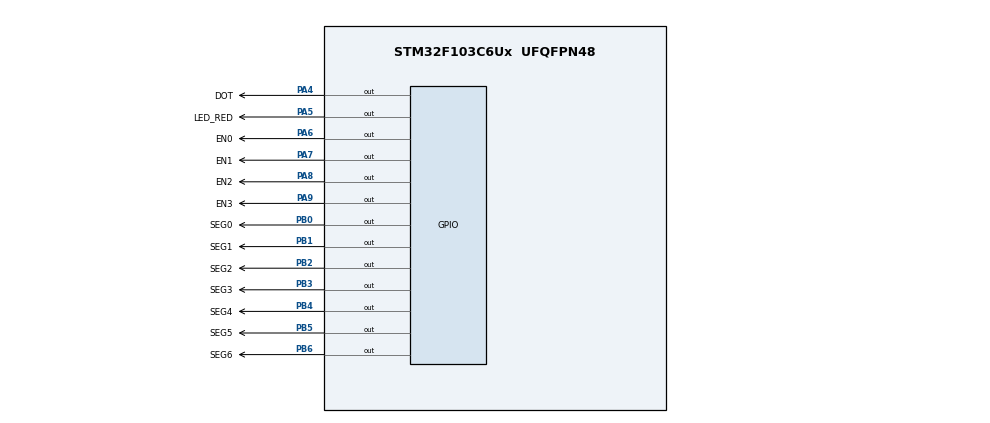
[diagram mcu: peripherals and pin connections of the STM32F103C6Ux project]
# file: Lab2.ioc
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Mcu.Family=STM32F1
Mcu.Name=STM32F103C6Ux
Mcu.Package=UFQFPN48
NVIC.PriorityGroup=NVIC_PRIORITYGROUP_4
NVIC.TIM2_IRQn=true\:0\:0\:false\:false\:true\:true\:true
PA4.GPIO_Label=DOT
PA4.Signal=GPIO_Output
PA5.GPIO_Label=LED_RED
PA5.Signal=GPIO_Output
PA6.GPIO_Label=EN0
PA6.Signal=GPIO_Output
PA7.GPIO_Label=EN1
PA7.Signal=GPIO_Output
PA8.GPIO_Label=EN2
PA8.Signal=GPIO_Output
PA9.GPIO_Label=EN3
PA9.Signal=GPIO_Output
PB0.GPIO_Label=SEG0
PB0.Signal=GPIO_Output
PB1.GPIO_Label=SEG1
PB1.Signal=GPIO_Output
PB2.GPIO_Label=SEG2
PB2.Signal=GPIO_Output
PB3.GPIO_Label=SEG3
PB3.Signal=GPIO_Output
PB4.GPIO_Label=SEG4
PB4.Signal=GPIO_Output
PB5.GPIO_Label=SEG5
PB5.Signal=GPIO_Output
PB6.GPIO_Label=SEG6
PB6.Signal=GPIO_Output
ProjectManager.HeapSize=0x200
ProjectManager.StackSize=0x400
ProjectManager.TargetToolchain=STM32CubeIDE
RCC.APB1Freq_Value=8000000
RCC.APB2Freq_Value=8000000
TIM2.Period=9
TIM2.Prescaler=7999
VP_SYS_VS_ND.Mode=No_Debug
VP_TIM2_VS_ClockSourceINT.Mode=Internal
board=custom

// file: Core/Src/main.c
/* USER CODE BEGIN Header */
/**
  ******************************************************************************
  * @file           : main.c
  * @brief          : Main program body
  ******************************************************************************
  * @attention
  *
  * <h2><center>&copy; Copyright (c) 2023 STMicroelectronics.
  * All rights reserved.</center></h2>
  *
  * This software component is licensed by ST under BSD 3-Clause license,
  * the "License"; You may not use this file except in compliance with the
  * License. You may obtain a copy of the License at:
  *                        opensource.org/licenses/BSD-3-Clause
  *
  ******************************************************************************
  */
/* USER CODE END Header */
#include "main.h"
#include "software_timer.h"

/* USER CODE BEGIN PM */
#define setLed 50 //led red 500ms
#define setDot 100 //1s
#define setSegment 50 //500ms
int status =1;
int counterLed = setLed;
int counterDot = setDot;
int counterSeg = setSegment;
const int MAX_LED = 4;
int index_led = 0;
int led_buffer[4] = {1,3,0,4};
int hour = 23, minute = 59, second = 55;
/* USER CODE END PM */

TIM_HandleTypeDef htim2;

void SystemClock_Config(void);
static void MX_GPIO_Init(void);
static void MX_TIM2_Init(void);

/* USER CODE BEGIN 0 */
void display7SEG (int counter){
	if(counter==0){
		HAL_GPIO_WritePin(SEG0_GPIO_Port, SEG0_Pin, RESET);
		HAL_GPIO_WritePin(SEG1_GPIO_Port, SEG1_Pin, RESET);
		HAL_GPIO_WritePin(SEG2_GPIO_Port, SEG2_Pin, RESET);
		HAL_GPIO_WritePin(SEG3_GPIO_Port, SEG3_Pin, RESET);
		HAL_GPIO_WritePin(SEG4_GPIO_Port, SEG4_Pin, RESET);
		HAL_GPIO_WritePin(SEG5_GPIO_Port, SEG5_Pin, RESET);
		HAL_GPIO_WritePin(SEG6_GPIO_Port, SEG6_Pin, SET);
	}
	if(counter==1){
		HAL_GPIO_WritePin(SEG0_GPIO_Port, SEG0_Pin, SET);
		HAL_GPIO_WritePin(SEG1_GPIO_Port, SEG1_Pin, RESET);
		HAL_GPIO_WritePin(SEG2_GPIO_Port, SEG2_Pin, RESET);
		HAL_GPIO_WritePin(SEG3_GPIO_Port, SEG3_Pin, SET);
		HAL_GPIO_WritePin(SEG4_GPIO_Port, SEG4_Pin, SET);
		HAL_GPIO_WritePin(SEG5_GPIO_Port, SEG5_Pin, SET);
		HAL_GPIO_WritePin(SEG6_GPIO_Port, SEG6_Pin, SET);
	}
	if(counter==2){
		HAL_GPIO_WritePin(SEG0_GPIO_Port, SEG0_Pin, RESET);
		HAL_GPIO_WritePin(SEG1_GPIO_Port, SEG1_Pin, RESET);
		HAL_GPIO_WritePin(SEG2_GPIO_Port, SEG2_Pin, SET);
		HAL_GPIO_WritePin(SEG3_GPIO_Port, SEG3_Pin, RESET);
		HAL_GPIO_WritePin(SEG4_GPIO_Port, SEG4_Pin, RESET);
		HAL_GPIO_WritePin(SEG5_GPIO_Port, SEG5_Pin, SET);
		HAL_GPIO_WritePin(SEG6_GPIO_Port, SEG6_Pin, RESET);
	}
	if(counter==3){
		HAL_GPIO_WritePin(SEG0_GPIO_Port, SEG0_Pin, RESET);
		HAL_GPIO_WritePin(SEG1_GPIO_Port, SEG1_Pin, RESET);
		HAL_GPIO_WritePin(SEG2_GPIO_Port, SEG2_Pin, RESET);
		HAL_GPIO_WritePin(SEG3_GPIO_Port, SEG3_Pin, RESET);
		HAL_GPIO_WritePin(SEG4_GPIO_Port, SEG4_Pin, SET);
		HAL_GPIO_WritePin(SEG5_GPIO_Port, SEG5_Pin, SET);
		HAL_GPIO_WritePin(SEG6_GPIO_Port, SEG6_Pin, RESET);
	}
	if(counter==4){
		HAL_GPIO_WritePin(SEG0_GPIO_Port, SEG0_Pin, SET);
		HAL_GPIO_WritePin(SEG1_GPIO_Port, SEG1_Pin, RESET);
		HAL_GPIO_WritePin(SEG2_GPIO_Port, SEG2_Pin, RESET);
		HAL_GPIO_WritePin(SEG3_GPIO_Port, SEG3_Pin, SET);
		HAL_GPIO_WritePin(SEG4_GPIO_Port, SEG4_Pin, SET);
		HAL_GPIO_WritePin(SEG5_GPIO_Port, SEG5_Pin, RESET);
		HAL_GPIO_WritePin(SEG6_GPIO_Port, SEG6_Pin, RESET);
	}
	if(counter==5){
		HAL_GPIO_WritePin(SEG0_GPIO_Port, SEG0_Pin, RESET);
		HAL_GPIO_WritePin(SEG1_GPIO_Port, SEG1_Pin, SET);
		HAL_GPIO_WritePin(SEG2_GPIO_Port, SEG2_Pin, RESET);
		HAL_GPIO_WritePin(SEG3_GPIO_Port, SEG3_Pin, RESET);
		HAL_GPIO_WritePin(SEG4_GPIO_Port, SEG4_Pin, SET);
		HAL_GPIO_WritePin(SEG5_GPIO_Port, SEG5_Pin, RESET);
		HAL_GPIO_WritePin(SEG6_GPIO_Port, SEG6_Pin, RESET);
	}
	if(counter==6){
		HAL_GPIO_WritePin(SEG0_GPIO_Port, SEG0_Pin, RESET);
		HAL_GPIO_WritePin(SEG1_GPIO_Port, SEG1_Pin, SET);
		HAL_GPIO_WritePin(SEG2_GPIO_Port, SEG2_Pin, RESET);
		HAL_GPIO_WritePin(SEG3_GPIO_Port, SEG3_Pin, RESET);
		HAL_GPIO_WritePin(SEG4_GPIO_Port, SEG4_Pin, RESET);
		HAL_GPIO_WritePin(SEG5_GPIO_Port, SEG5_Pin, RESET);
		HAL_GPIO_WritePin(SEG6_GPIO_Port, SEG6_Pin, RESET);
	}
	if(counter==7){
		HAL_GPIO_WritePin(SEG0_GPIO_Port, SEG0_Pin, RESET);
		HAL_GPIO_WritePin(SEG1_GPIO_Port, SEG1_Pin, RESET);
		HAL_GPIO_WritePin(SEG2_GPIO_Port, SEG2_Pin, RESET);
		HAL_GPIO_WritePin(SEG3_GPIO_Port, SEG3_Pin, SET);
		HAL_GPIO_WritePin(SEG4_GPIO_Port, SEG4_Pin, SET);
		HAL_GPIO_WritePin(SEG5_GPIO_Port, SEG5_Pin, SET);
		HAL_GPIO_WritePin(SEG6_GPIO_Port, SEG6_Pin, SET);
	}
	if(counter==8){
		HAL_GPIO_WritePin(SEG0_GPIO_Port, SEG0_Pin, RESET);
		HAL_GPIO_WritePin(SEG1_GPIO_Port, SEG1_Pin, RESET);
		HAL_GPIO_WritePin(SEG2_GPIO_Port, SEG2_Pin, RESET);
		HAL_GPIO_WritePin(SEG3_GPIO_Port, SEG3_Pin, RESET);
		HAL_GPIO_WritePin(SEG4_GPIO_Port, SEG4_Pin, RESET);
		HAL_GPIO_WritePin(SEG5_GPIO_Port, SEG5_Pin, RESET);
		HAL_GPIO_WritePin(SEG6_GPIO_Port, SEG6_Pin, RESET);
	}
	if(counter==9){
		HAL_GPIO_WritePin(SEG0_GPIO_Port, SEG0_Pin, RESET);
		HAL_GPIO_WritePin(SEG1_GPIO_Port, SEG1_Pin, RESET);
		HAL_GPIO_WritePin(SEG2_GPIO_Port, SEG2_Pin, RESET);
		HAL_GPIO_WritePin(SEG3_GPIO_Port, SEG3_Pin, RESET);
		HAL_GPIO_WritePin(SEG4_GPIO_Port, SEG4_Pin, SET);
		HAL_GPIO_WritePin(SEG5_GPIO_Port, SEG5_Pin, RESET);
		HAL_GPIO_WritePin(SEG6_GPIO_Port, SEG6_Pin, RESET);
	}
}
void updateClockBuffer(){
	led_buffer[0] = hour/10;
	led_buffer[1] = hour%10;
	led_buffer[2] = minute/10;
	led_buffer[3] = minute%10;
}

void update7SEG(int index){
	display7SEG(led_buffer[index]);
    switch (index){
	case 0:
		// Display the first 7 SEG with led_buffer [0]
		HAL_GPIO_WritePin(EN0_GPIO_Port, EN0_Pin, RESET);
		HAL_GPIO_WritePin(EN1_GPIO_Port, EN1_Pin, SET);
		HAL_GPIO_WritePin(EN2_GPIO_Port, EN2_Pin, SET);
		HAL_GPIO_WritePin(EN3_GPIO_Port, EN3_Pin, SET);
		break ;
	case 1:
		// Display the second 7 SEG with led_buffer [1]
		HAL_GPIO_WritePin(EN0_GPIO_Port, EN0_Pin, SET);
		HAL_GPIO_WritePin(EN1_GPIO_Port, EN1_Pin, RESET);
		HAL_GPIO_WritePin(EN2_GPIO_Port, EN2_Pin, SET);
		HAL_GPIO_WritePin(EN3_GPIO_Port, EN3_Pin, SET);
		break ;
	case 2:
		// Display the third 7 SEG with led_buffer [2]
		HAL_GPIO_WritePin(EN0_GPIO_Port, EN0_Pin, SET);
		HAL_GPIO_WritePin(EN1_GPIO_Port, EN1_Pin, SET);
		HAL_GPIO_WritePin(EN2_GPIO_Port, EN2_Pin, RESET);
		HAL_GPIO_WritePin(EN3_GPIO_Port, EN3_Pin, SET);
		break ;
	case 3:
		// Display the forth 7 SEG with led_buffer [3]
		HAL_GPIO_WritePin(EN0_GPIO_Port, EN0_Pin, SET);
		HAL_GPIO_WritePin(EN1_GPIO_Port, EN1_Pin, SET);
		HAL_GPIO_WritePin(EN2_GPIO_Port, EN2_Pin, SET);
		HAL_GPIO_WritePin(EN3_GPIO_Port, EN3_Pin, RESET);
		break ;
	default :
		break ;
	}
}
const int MAX_LED_MATRIX = 8;
int index_led_matrix = 0;
uint8_t matrix_buffer[8] = {0x01, 0x02, 0x03, 0x04, 0x05, 0x06, 0x07, 0x08};
void updateLEDMatrix(int index){
    switch (index){
        case 0:
        	//ENMx
        	HAL_GPIO_WritePin(ENM0_GPIO_Port, ENM0_Pin, RESET);
        	HAL_GPIO_WritePin(ENM1_GPIO_Port, ENM1_Pin, SET);
        	HAL_GPIO_WritePin(ENM2_GPIO_Port, ENM2_Pin, SET);
        	HAL_GPIO_WritePin(ENM3_GPIO_Port, ENM3_Pin, SET);
        	HAL_GPIO_WritePin(ENM4_GPIO_Port, ENM4_Pin, SET);
        	HAL_GPIO_WritePin(ENM5_GPIO_Port, ENM5_Pin, SET);
        	HAL_GPIO_WritePin(ENM6_GPIO_Port, ENM6_Pin, SET);
        	HAL_GPIO_WritePin(ENM7_GPIO_Port, ENM7_Pin, SET);
        	//ROWx
        	HAL_GPIO_WritePin(ROW0_GPIO_Port, ROW0_Pin, SET);
        	HAL_GPIO_WritePin(ROW1_GPIO_Port, ROW1_Pin, SET);
        	HAL_GPIO_WritePin(ROW2_GPIO_Port, ROW2_Pin, SET);
        	HAL_GPIO_WritePin(ROW3_GPIO_Port, ROW3_Pin, SET);
        	HAL_GPIO_WritePin(ROW4_GPIO_Port, ROW4_Pin, SET);
        	HAL_GPIO_WritePin(ROW5_GPIO_Port, ROW5_Pin, SET);
        	HAL_GPIO_WritePin(ROW6_GPIO_Port, ROW6_Pin, SET);
        	HAL_GPIO_WritePin(ROW7_GPIO_Port, ROW7_Pin, SET);
            break;
        case 1:
        	//ENMx
        	HAL_GPIO_WritePin(ENM0_GPIO_Port, ENM0_Pin, SET);
        	HAL_GPIO_WritePin(ENM1_GPIO_Port, ENM1_Pin, RESET);
        	HAL_GPIO_WritePin(ENM2_GPIO_Port, ENM2_Pin, SET);
        	HAL_GPIO_WritePin(ENM3_GPIO_Port, ENM3_Pin, SET);
        	HAL_GPIO_WritePin(ENM4_GPIO_Port, ENM4_Pin, SET);
        	HAL_GPIO_WritePin(ENM5_GPIO_Port, ENM5_Pin, SET);
        	HAL_GPIO_WritePin(ENM6_GPIO_Port, ENM6_Pin, SET);
        	HAL_GPIO_WritePin(ENM7_GPIO_Port, ENM7_Pin, SET);
        	//ROWx
        	HAL_GPIO_WritePin(ROW0_GPIO_Port, ROW0_Pin, SET);
        	HAL_GPIO_WritePin(ROW1_GPIO_Port, ROW1_Pin, RESET);
        	HAL_GPIO_WritePin(ROW2_GPIO_Port, ROW2_Pin, RESET);
        	HAL_GPIO_WritePin(ROW3_GPIO_Port, ROW3_Pin, RESET);
        	HAL_GPIO_WritePin(ROW4_GPIO_Port, ROW4_Pin, RESET);
        	HAL_GPIO_WritePin(ROW5_GPIO_Port, ROW5_Pin, RESET);
        	HAL_GPIO_WritePin(ROW6_GPIO_Port, ROW6_Pin, RESET);
        	HAL_GPIO_WritePin(ROW7_GPIO_Port, ROW7_Pin, RESET);
            break;
        case 2:
        	//ENMx
        	HAL_GPIO_WritePin(ENM0_GPIO_Port, ENM0_Pin, SET);
        	HAL_GPIO_WritePin(ENM1_GPIO_Port, ENM1_Pin, SET);
        	HAL_GPIO_WritePin(ENM2_GPIO_Port, ENM2_Pin, RESET);
        	HAL_GPIO_WritePin(ENM3_GPIO_Port, ENM3_Pin, SET);
        	HAL_GPIO_WritePin(ENM4_GPIO_Port, ENM4_Pin, SET);
        	HAL_GPIO_WritePin(ENM5_GPIO_Port, ENM5_Pin, SET);
        	HAL_GPIO_WritePin(ENM6_GPIO_Port, ENM6_Pin, SET);
        	HAL_GPIO_WritePin(ENM7_GPIO_Port, ENM7_Pin, SET);
        	//ROWx
        	HAL_GPIO_WritePin(ROW0_GPIO_Port, ROW0_Pin, RESET);
        	HAL_GPIO_WritePin(ROW1_GPIO_Port, ROW1_Pin, SET);
        	HAL_GPIO_WritePin(ROW2_GPIO_Port, ROW2_Pin, SET);
        	HAL_GPIO_WritePin(ROW3_GPIO_Port, ROW3_Pin, SET);
        	HAL_GPIO_WritePin(ROW4_GPIO_Port, ROW4_Pin, RESET);
        	HAL_GPIO_WritePin(ROW5_GPIO_Port, ROW5_Pin, SET);
        	HAL_GPIO_WritePin(ROW6_GPIO_Port, ROW6_Pin, SET);
        	HAL_GPIO_WritePin(ROW7_GPIO_Port, ROW7_Pin, SET);
            break;
        case 3:
        	//ENMx
        	HAL_GPIO_WritePin(ENM0_GPIO_Port, ENM0_Pin, SET);
        	HAL_GPIO_WritePin(ENM1_GPIO_Port, ENM1_Pin, SET);
        	HAL_GPIO_WritePin(ENM2_GPIO_Port, ENM2_Pin, SET);
        	HAL_GPIO_WritePin(ENM3_GPIO_Port, ENM3_Pin, RESET);
        	HAL_GPIO_WritePin(ENM4_GPIO_Port, ENM4_Pin, SET);
        	HAL_GPIO_WritePin(ENM5_GPIO_Port, ENM5_Pin, SET);
        	HAL_GPIO_WritePin(ENM6_GPIO_Port, ENM6_Pin, SET);
        	HAL_GPIO_WritePin(ENM7_GPIO_Port, ENM7_Pin, SET);
        	//ROWx
        	HAL_GPIO_WritePin(ROW0_GPIO_Port, ROW0_Pin, RESET);
        	HAL_GPIO_WritePin(ROW1_GPIO_Port, ROW1_Pin, SET);
        	HAL_GPIO_WritePin(ROW2_GPIO_Port, ROW2_Pin, SET);
        	HAL_GPIO_WritePin(ROW3_GPIO_Port, ROW3_Pin, SET);
        	HAL_GPIO_WritePin(ROW4_GPIO_Port, ROW4_Pin, RESET);
        	HAL_GPIO_WritePin(ROW5_GPIO_Port, ROW5_Pin, SET);
        	HAL_GPIO_WritePin(ROW6_GPIO_Port, ROW6_Pin, SET);
        	HAL_GPIO_WritePin(ROW7_GPIO_Port, ROW7_Pin, SET);
            break;
        case 4:
        	//ENMx
        	HAL_GPIO_WritePin(ENM0_GPIO_Port, ENM0_Pin, SET);
        	HAL_GPIO_WritePin(ENM1_GPIO_Port, ENM1_Pin, SET);
        	HAL_GPIO_WritePin(ENM2_GPIO_Port, ENM2_Pin, SET);
        	HAL_GPIO_WritePin(ENM3_GPIO_Port, ENM3_Pin, SET);
        	HAL_GPIO_WritePin(ENM4_GPIO_Port, ENM4_Pin, RESET);
        	HAL_GPIO_WritePin(ENM5_GPIO_Port, ENM5_Pin, SET);
        	HAL_GPIO_WritePin(ENM6_GPIO_Port, ENM6_Pin, SET);
        	HAL_GPIO_WritePin(ENM7_GPIO_Port, ENM7_Pin, SET);
        	//ROWx
        	HAL_GPIO_WritePin(ROW0_GPIO_Port, ROW0_Pin, RESET);
        	HAL_GPIO_WritePin(ROW1_GPIO_Port, ROW1_Pin, SET);
        	HAL_GPIO_WritePin(ROW2_GPIO_Port, ROW2_Pin, SET);
        	HAL_GPIO_WritePin(ROW3_GPIO_Port, ROW3_Pin, SET);
        	HAL_GPIO_WritePin(ROW4_GPIO_Port, ROW4_Pin, RESET);
        	HAL_GPIO_WritePin(ROW5_GPIO_Port, ROW5_Pin, SET);
        	HAL_GPIO_WritePin(ROW6_GPIO_Port, ROW6_Pin, SET);
        	HAL_GPIO_WritePin(ROW7_GPIO_Port, ROW7_Pin, SET);
            break;
        case 5:
        	//ENMx
        	HAL_GPIO_WritePin(ENM0_GPIO_Port, ENM0_Pin, SET);
        	HAL_GPIO_WritePin(ENM1_GPIO_Port, ENM1_Pin, SET);
        	HAL_GPIO_WritePin(ENM2_GPIO_Port, ENM2_Pin, SET);
        	HAL_GPIO_WritePin(ENM3_GPIO_Port, ENM3_Pin, SET);
        	HAL_GPIO_WritePin(ENM4_GPIO_Port, ENM4_Pin, SET);
        	HAL_GPIO_WritePin(ENM5_GPIO_Port, ENM5_Pin, RESET);
        	HAL_GPIO_WritePin(ENM6_GPIO_Port, ENM6_Pin, SET);
        	HAL_GPIO_WritePin(ENM7_GPIO_Port, ENM7_Pin, SET);
        	//ROWx
        	HAL_GPIO_WritePin(ROW0_GPIO_Port, ROW0_Pin, RESET);
        	HAL_GPIO_WritePin(ROW1_GPIO_Port, ROW1_Pin, SET);
        	HAL_GPIO_WritePin(ROW2_GPIO_Port, ROW2_Pin, SET);
        	HAL_GPIO_WritePin(ROW3_GPIO_Port, ROW3_Pin, SET);
        	HAL_GPIO_WritePin(ROW4_GPIO_Port, ROW4_Pin, RESET);
        	HAL_GPIO_WritePin(ROW5_GPIO_Port, ROW5_Pin, SET);
        	HAL_GPIO_WritePin(ROW6_GPIO_Port, ROW6_Pin, SET);
        	HAL_GPIO_WritePin(ROW7_GPIO_Port, ROW7_Pin, SET);
            break;
        case 6:
        	//ENMx
        	HAL_GPIO_WritePin(ENM0_GPIO_Port, ENM0_Pin, SET);
        	HAL_GPIO_WritePin(ENM1_GPIO_Port, ENM1_Pin, SET);
        	HAL_GPIO_WritePin(ENM2_GPIO_Port, ENM2_Pin, SET);
        	HAL_GPIO_WritePin(ENM3_GPIO_Port, ENM3_Pin, SET);
        	HAL_GPIO_WritePin(ENM4_GPIO_Port, ENM4_Pin, SET);
        	HAL_GPIO_WritePin(ENM5_GPIO_Port, ENM5_Pin, SET);
        	HAL_GPIO_WritePin(ENM6_GPIO_Port, ENM6_Pin, RESET);
        	HAL_GPIO_WritePin(ENM7_GPIO_Port, ENM7_Pin, SET);
        	//ROWx
        	HAL_GPIO_WritePin(ROW0_GPIO_Port, ROW0_Pin, SET);
        	HAL_GPIO_WritePin(ROW1_GPIO_Port, ROW1_Pin, RESET);
        	HAL_GPIO_WritePin(ROW2_GPIO_Port, ROW2_Pin, RESET);
        	HAL_GPIO_WritePin(ROW3_GPIO_Port, ROW3_Pin, RESET);
        	HAL_GPIO_WritePin(ROW4_GPIO_Port, ROW4_Pin, RESET);
        	HAL_GPIO_WritePin(ROW5_GPIO_Port, ROW5_Pin, RESET);
        	HAL_GPIO_WritePin(ROW6_GPIO_Port, ROW6_Pin, RESET);
        	HAL_GPIO_WritePin(ROW7_GPIO_Port, ROW7_Pin, RESET);
            break;
        case 7:
        	//ENMx
        	HAL_GPIO_WritePin(ENM0_GPIO_Port, ENM0_Pin, SET);
        	HAL_GPIO_WritePin(ENM1_GPIO_Port, ENM1_Pin, SET);
        	HAL_GPIO_WritePin(ENM2_GPIO_Port, ENM2_Pin, SET);
        	HAL_GPIO_WritePin(ENM3_GPIO_Port, ENM3_Pin, SET);
        	HAL_GPIO_WritePin(ENM4_GPIO_Port, ENM4_Pin, SET);
        	HAL_GPIO_WritePin(ENM5_GPIO_Port, ENM5_Pin, SET);
        	HAL_GPIO_WritePin(ENM6_GPIO_Port, ENM6_Pin, SET);
        	HAL_GPIO_WritePin(ENM7_GPIO_Port, ENM7_Pin, RESET);
        	//ROWx
        	HAL_GPIO_WritePin(ROW0_GPIO_Port, ROW0_Pin, SET);
        	HAL_GPIO_WritePin(ROW1_GPIO_Port, ROW1_Pin, SET);
        	HAL_GPIO_WritePin(ROW2_GPIO_Port, ROW2_Pin, SET);
        	HAL_GPIO_WritePin(ROW3_GPIO_Port, ROW3_Pin, SET);
        	HAL_GPIO_WritePin(ROW4_GPIO_Port, ROW4_Pin, SET);
        	HAL_GPIO_WritePin(ROW5_GPIO_Port, ROW5_Pin, SET);
        	HAL_GPIO_WritePin(ROW6_GPIO_Port, ROW6_Pin, SET);
        	HAL_GPIO_WritePin(ROW7_GPIO_Port, ROW7_Pin, SET);
            break;
        default:
            break;
    }
}
/* USER CODE END 0 */

int main(void)
{

  /* MCU Configuration--------------------------------------------------------*/

  /* Reset of all peripherals, Initializes the Flash interface and the Systick. */
  HAL_Init();

  /* Configure the system clock */
  SystemClock_Config();

  /* Initialize all configured peripherals */
  MX_GPIO_Init();
  MX_TIM2_Init();
  /* USER CODE BEGIN 2 */
  HAL_TIM_Base_Start_IT (& htim2 );
  /* USER CODE END 2 */

  /* Infinite loop */
  /* USER CODE BEGIN WHILE */
  setTimer0(1000);
  setTimer1(500);
  setTimer2(10);
  updateClockBuffer();
  while (1)
  {
	    if(timer0_flag == 1){
	        setTimer0(1000);
	        //TODO
	        second++;
	        if (second >= 60){
	            second = 0;
	            minute++;
	        }
	        if(minute >= 60){
	            minute = 0;
	            hour++;
	        }
	        if(hour >=24){
	            hour = 0;
	        }
	        updateClockBuffer();
	        HAL_GPIO_TogglePin(DOT_GPIO_Port, DOT_Pin);
	    }
	    if(timer1_flag == 1){
	    	setTimer1(500);
	    	//TODO
    		HAL_GPIO_TogglePin(LED_RED_GPIO_Port, LED_RED_Pin);
    		if(index_led > 3){
    			index_led=0;
    		}
    		update7SEG(index_led++);
	    }
	    if(timer2_flag==1){
	    	setTimer2(10);
	    	//TODO
			  updateLEDMatrix(index_led_matrix);
			  index_led_matrix++;
			  if(index_led_matrix >= 8)
			  {
				  index_led_matrix = 0;
			  }
	    }
    /* USER CODE END WHILE */

  }
}

void SystemClock_Config(void)
{
  RCC_OscInitTypeDef RCC_OscInitStruct = {0};
  RCC_ClkInitTypeDef RCC_ClkInitStruct = {0};

  /** Initializes the RCC Oscillators according to the specified parameters
  * in the RCC_OscInitTypeDef structure.
  */
  RCC_OscInitStruct.OscillatorType = RCC_OSCILLATORTYPE_HSI;
  RCC_OscInitStruct.HSIState = RCC_HSI_ON;
  RCC_OscInitStruct.HSICalibrationValue = RCC_HSICALIBRATION_DEFAULT;
  RCC_OscInitStruct.PLL.PLLState = RCC_PLL_NONE;
  if (HAL_RCC_OscConfig(&RCC_OscInitStruct) != HAL_OK)
  {
    Error_Handler();
  }
  /** Initializes the CPU, AHB and APB buses clocks
  */
  RCC_ClkInitStruct.ClockType = RCC_CLOCKTYPE_HCLK|RCC_CLOCKTYPE_SYSCLK
                              |RCC_CLOCKTYPE_PCLK1|RCC_CLOCKTYPE_PCLK2;
  RCC_ClkInitStruct.SYSCLKSource = RCC_SYSCLKSOURCE_HSI;
  RCC_ClkInitStruct.AHBCLKDivider = RCC_SYSCLK_DIV1;
  RCC_ClkInitStruct.APB1CLKDivider = RCC_HCLK_DIV1;
  RCC_ClkInitStruct.APB2CLKDivider = RCC_HCLK_DIV1;

  if (HAL_RCC_ClockConfig(&RCC_ClkInitStruct, FLASH_LATENCY_0) != HAL_OK)
  {
    Error_Handler();
  }
}

static void MX_TIM2_Init(void)
{

  TIM_ClockConfigTypeDef sClockSourceConfig = {0};
  TIM_MasterConfigTypeDef sMasterConfig = {0};

  htim2.Instance = TIM2;
  htim2.Init.Prescaler = 7999;
  htim2.Init.CounterMode = TIM_COUNTERMODE_UP;
  htim2.Init.Period = 9;
  htim2.Init.ClockDivision = TIM_CLOCKDIVISION_DIV1;
  htim2.Init.AutoReloadPreload = TIM_AUTORELOAD_PRELOAD_DISABLE;
  if (HAL_TIM_Base_Init(&htim2) != HAL_OK)
  {
    Error_Handler();
  }
  sClockSourceConfig.ClockSource = TIM_CLOCKSOURCE_INTERNAL;
  if (HAL_TIM_ConfigClockSource(&htim2, &sClockSourceConfig) != HAL_OK)
  {
    Error_Handler();
  }
  sMasterConfig.MasterOutputTrigger = TIM_TRGO_RESET;
  sMasterConfig.MasterSlaveMode = TIM_MASTERSLAVEMODE_DISABLE;
  if (HAL_TIMEx_MasterConfigSynchronization(&htim2, &sMasterConfig) != HAL_OK)
  {
    Error_Handler();
  }

}

static void MX_GPIO_Init(void)
{
  GPIO_InitTypeDef GPIO_InitStruct = {0};

  /* GPIO Ports Clock Enable */
  __HAL_RCC_GPIOA_CLK_ENABLE();
  __HAL_RCC_GPIOB_CLK_ENABLE();

  /*Configure GPIO pin Output Level */
  HAL_GPIO_WritePin(GPIOA, ENM0_Pin|ENM1_Pin|DOT_Pin|LED_RED_Pin
                          |EN0_Pin|EN1_Pin|EN2_Pin|EN3_Pin
                          |ENM2_Pin|ENM3_Pin|ENM4_Pin|ENM5_Pin
                          |ENM6_Pin|ENM7_Pin, GPIO_PIN_RESET);

  /*Configure GPIO pin Output Level */
  HAL_GPIO_WritePin(GPIOB, SEG0_Pin|SEG1_Pin|SEG2_Pin|ROW2_Pin
                          |ROW3_Pin|ROW4_Pin|ROW5_Pin|ROW6_Pin
                          |ROW7_Pin|SEG3_Pin|SEG4_Pin|SEG5_Pin
                          |SEG6_Pin|ROW0_Pin|ROW1_Pin, GPIO_PIN_RESET);

  /*Configure GPIO pins : ENM0_Pin ENM1_Pin DOT_Pin LED_RED_Pin
                           EN0_Pin EN1_Pin EN2_Pin EN3_Pin
                           ENM2_Pin ENM3_Pin ENM4_Pin ENM5_Pin
                           ENM6_Pin ENM7_Pin */
  GPIO_InitStruct.Pin = ENM0_Pin|ENM1_Pin|DOT_Pin|LED_RED_Pin
                          |EN0_Pin|EN1_Pin|EN2_Pin|EN3_Pin
                          |ENM2_Pin|ENM3_Pin|ENM4_Pin|ENM5_Pin
                          |ENM6_Pin|ENM7_Pin;
  GPIO_InitStruct.Mode = GPIO_MODE_OUTPUT_PP;
  GPIO_InitStruct.Pull = GPIO_NOPULL;
  GPIO_InitStruct.Speed = GPIO_SPEED_FREQ_LOW;
  HAL_GPIO_Init(GPIOA, &GPIO_InitStruct);

  /*Configure GPIO pins : SEG0_Pin SEG1_Pin SEG2_Pin ROW2_Pin
                           ROW3_Pin ROW4_Pin ROW5_Pin ROW6_Pin
                           ROW7_Pin SEG3_Pin SEG4_Pin SEG5_Pin
                           SEG6_Pin ROW0_Pin ROW1_Pin */
  GPIO_InitStruct.Pin = SEG0_Pin|SEG1_Pin|SEG2_Pin|ROW2_Pin
                          |ROW3_Pin|ROW4_Pin|ROW5_Pin|ROW6_Pin
                          |ROW7_Pin|SEG3_Pin|SEG4_Pin|SEG5_Pin
                          |SEG6_Pin|ROW0_Pin|ROW1_Pin;
  GPIO_InitStruct.Mode = GPIO_MODE_OUTPUT_PP;
  GPIO_InitStruct.Pull = GPIO_NOPULL;
  GPIO_InitStruct.Speed = GPIO_SPEED_FREQ_LOW;
  HAL_GPIO_Init(GPIOB, &GPIO_InitStruct);

}

/* USER CODE BEGIN 4 */
void HAL_TIM_PeriodElapsedCallback( TIM_HandleTypeDef * htim ){
	timer_run();
}
/* USER CODE END 4 */

void Error_Handler(void)
{
  __disable_irq();
  while (1)
  {
  }
}

/************************ (C) COPYRIGHT STMicroelectronics *****END OF FILE****/
